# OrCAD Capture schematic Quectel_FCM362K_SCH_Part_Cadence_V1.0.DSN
size A1

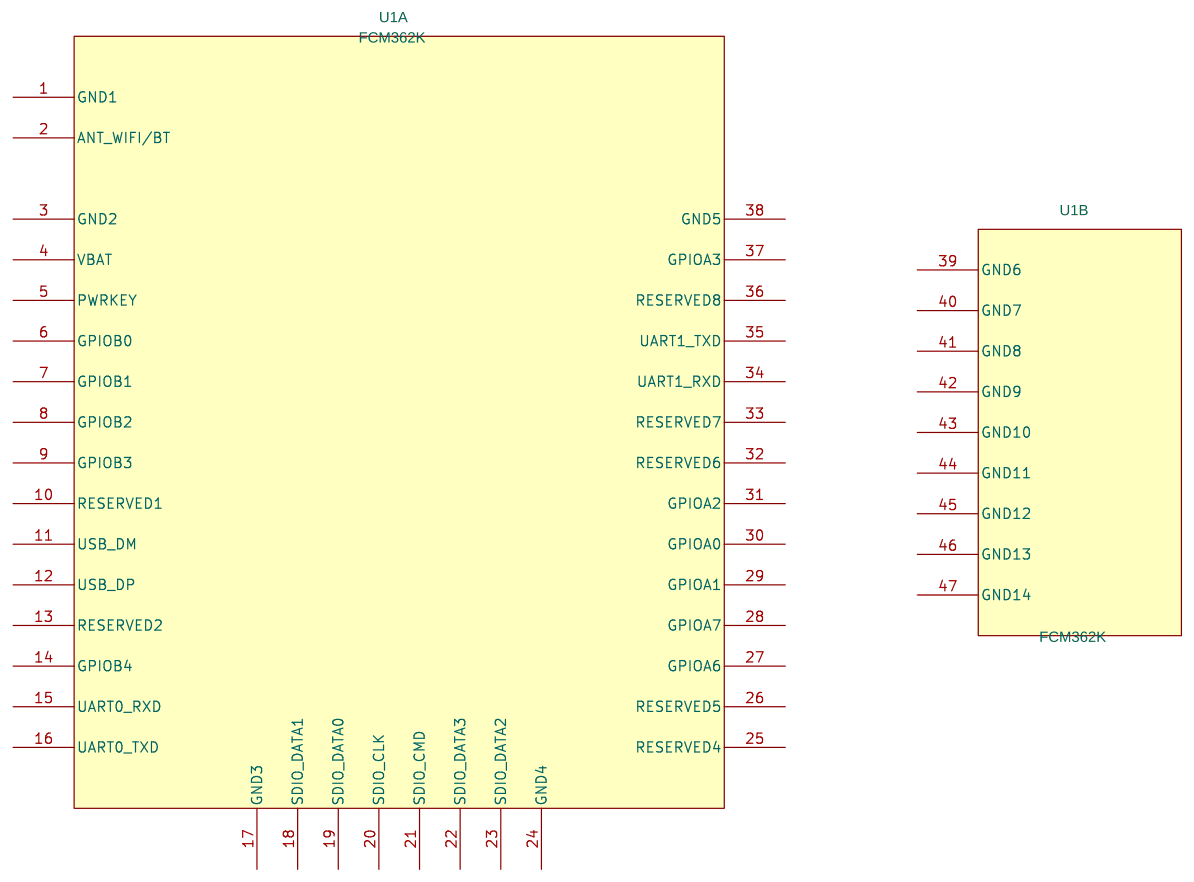
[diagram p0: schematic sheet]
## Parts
U1  FCM362K  [FCM362K]  (sections A,B)

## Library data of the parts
U1 = FCM362K

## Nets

Not connected (* = marked no-connect by the designer): U1 1(GND1) 2(ANT_WIFI/BT) 3(GND2) 4(VBAT) 5(PWRKEY) 6(GPIOB0) 7(GPIOB1) 8(GPIOB2) 9(GPIOB3) 10(RESERVED1) 11(USB_DM) 12(USB_DP) 13(RESERVED2) 14(GPIOB4) 15(UART0_RXD) 16(UART0_TXD) 17(GND3) 18(SDIO_DATA1) 19(SDIO_DATA0) 20(SDIO_CLK) 21(SDIO_CMD) 22(SDIO_DATA3) 23(SDIO_DATA2) 24(GND4) 25(RESERVED4) 26(RESERVED5) 27(GPIOA6) 28(GPIOA7) 29(GPIOA1) 30(GPIOA0) 31(GPIOA2) 32(RESERVED6) 33(RESERVED7) 34(UART1_RXD) 35(UART1_TXD) 36(RESERVED8) 37(GPIOA3) 38(GND5) 39(GND6) 40(GND7) 41(GND8) 42(GND9) 43(GND10) 44(GND11) 45(GND12) 46(GND13) 47(GND14)
